VERSION 5.8 ;
NAMESCASESENSITIVE ON ;
UNITS
  DATABASE MICRONS 100 ;
END UNITS
MANUFACTURINGGRID 0.01 ;

SITE CORE
  CLASS CORE ;
  SIZE 1.000 BY 1.000 ;
END CORE

LAYER M1
  TYPE ROUTING ;
  DIRECTION HORIZONTAL ;
  PITCH 0.20 ;
  WIDTH 0.10 ;
END M1

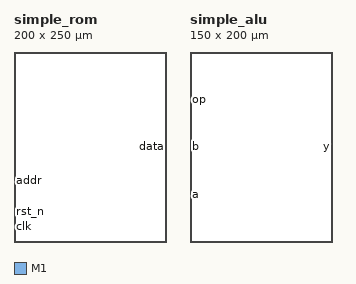
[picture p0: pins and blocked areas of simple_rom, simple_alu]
MACRO simple_rom
  CLASS BLOCK ;
  ORIGIN 0 0 ;
  SIZE 200.000 BY 250.000 ;
  SYMMETRY X Y ;
  SITE CORE ;

  PIN clk
    DIRECTION INPUT ;
    USE SIGNAL ;
    PORT
      LAYER M1 ;
        RECT 0.000 20.000 1.000 21.000 ;
    END
  END clk

  PIN rst_n
    DIRECTION INPUT ;
    USE SIGNAL ;
    PORT
      LAYER M1 ;
        RECT 0.000 40.000 1.000 41.000 ;
    END
  END rst_n

  PIN addr
    DIRECTION INPUT ;
    USE SIGNAL ;
    PORT
      LAYER M1 ;
        RECT 0.000 80.000 1.000 81.000 ;
    END
  END addr

  PIN data
    DIRECTION OUTPUT ;
    USE SIGNAL ;
    PORT
      LAYER M1 ;
        RECT 199.000 125.000 200.000 126.000 ;
    END
  END data

END simple_rom

MACRO simple_alu
  CLASS BLOCK ;
  ORIGIN 0 0 ;
  SIZE 150.000 BY 200.000 ;
  SYMMETRY X Y ;
  SITE CORE ;

  PIN a
    DIRECTION INPUT ;
    USE SIGNAL ;
    PORT
      LAYER M1 ;
        RECT 0.000 50.000 1.000 51.000 ;
    END
  END a

  PIN b
    DIRECTION INPUT ;
    USE SIGNAL ;
    PORT
      LAYER M1 ;
        RECT 0.000 100.000 1.000 101.000 ;
    END
  END b

  PIN op
    DIRECTION INPUT ;
    USE SIGNAL ;
    PORT
      LAYER M1 ;
        RECT 0.000 150.000 1.000 151.000 ;
    END
  END op

  PIN y
    DIRECTION OUTPUT ;
    USE SIGNAL ;
    PORT
      LAYER M1 ;
        RECT 149.000 100.000 150.000 101.000 ;
    END
  END y

END simple_alu

END LIBRARY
